VERSION 5.8 ;
BUSBITCHARS "[]" ;
DIVIDERCHAR "/" ;
UNITS
    DATABASE MICRONS 1000 ;
END UNITS

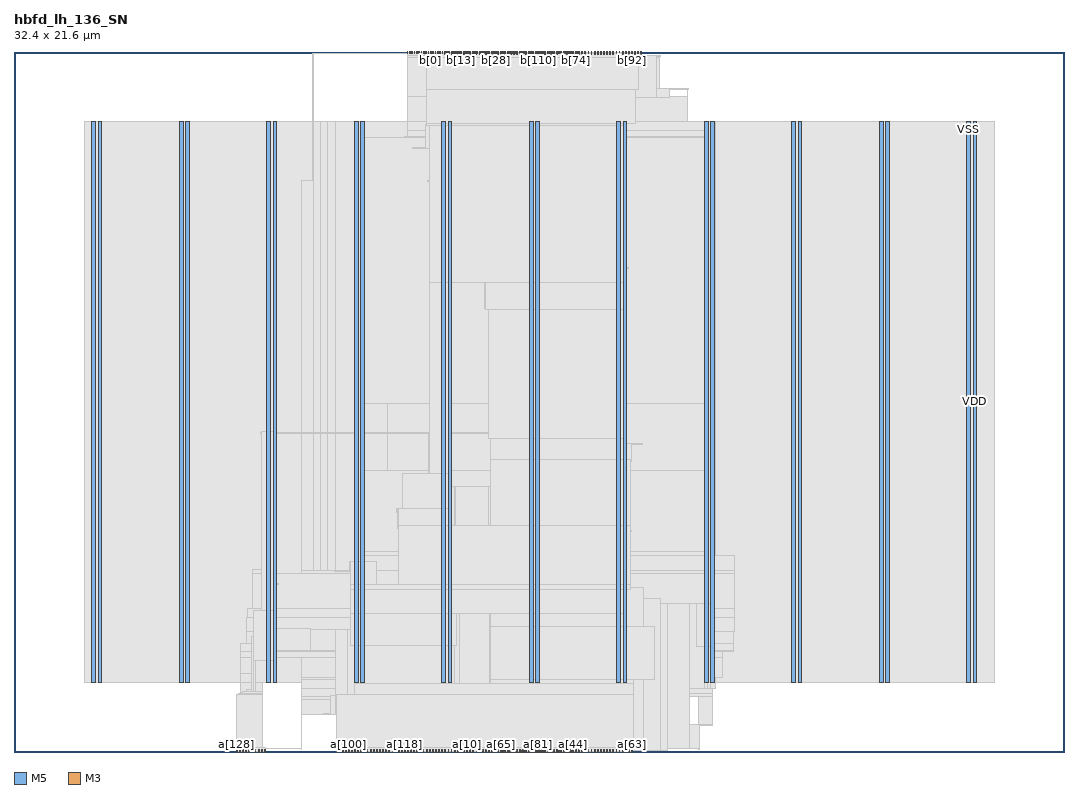
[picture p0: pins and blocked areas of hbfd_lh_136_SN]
MACRO hbfd_lh_136_SN
  FOREIGN hbfd_lh_136_SN 0 0 ;
  CLASS BLOCK ;
  SIZE 32.4 BY 21.6 ;
  PIN a[0]
    DIRECTION INPUT ;
    USE SIGNAL ;
    PORT
      LAYER M5 ;
        RECT  13.008 0 13.032 0.084 ;
    END
  END a[0]
  PIN a[100]
    DIRECTION INPUT ;
    USE SIGNAL ;
    PORT
      LAYER M5 ;
        RECT  10.32 0 10.344 0.084 ;
    END
  END a[100]
  PIN a[101]
    DIRECTION INPUT ;
    USE SIGNAL ;
    PORT
      LAYER M5 ;
        RECT  10.416 0 10.44 0.084 ;
    END
  END a[101]
  PIN a[102]
    DIRECTION INPUT ;
    USE SIGNAL ;
    PORT
      LAYER M5 ;
        RECT  10.512 0 10.536 0.084 ;
    END
  END a[102]
  PIN a[103]
    DIRECTION INPUT ;
    USE SIGNAL ;
    PORT
      LAYER M5 ;
        RECT  10.608 0 10.632 0.084 ;
    END
  END a[103]
  PIN a[104]
    DIRECTION INPUT ;
    USE SIGNAL ;
    PORT
      LAYER M5 ;
        RECT  10.704 0 10.728 0.084 ;
    END
  END a[104]
  PIN a[105]
    DIRECTION INPUT ;
    USE SIGNAL ;
    PORT
      LAYER M5 ;
        RECT  10.8 0 10.824 0.084 ;
    END
  END a[105]
  PIN a[106]
    DIRECTION INPUT ;
    USE SIGNAL ;
    PORT
      LAYER M5 ;
        RECT  10.896 0 10.92 0.084 ;
    END
  END a[106]
  PIN a[107]
    DIRECTION INPUT ;
    USE SIGNAL ;
    PORT
      LAYER M5 ;
        RECT  10.992 0 11.016 0.084 ;
    END
  END a[107]
  PIN a[108]
    DIRECTION INPUT ;
    USE SIGNAL ;
    PORT
      LAYER M5 ;
        RECT  11.088 0 11.112 0.084 ;
    END
  END a[108]
  PIN a[109]
    DIRECTION INPUT ;
    USE SIGNAL ;
    PORT
      LAYER M5 ;
        RECT  11.184 0 11.208 0.084 ;
    END
  END a[109]
  PIN a[10]
    DIRECTION INPUT ;
    USE SIGNAL ;
    PORT
      LAYER M5 ;
        RECT  13.968 0 13.992 0.084 ;
    END
  END a[10]
  PIN a[110]
    DIRECTION INPUT ;
    USE SIGNAL ;
    PORT
      LAYER M5 ;
        RECT  11.28 0 11.304 0.084 ;
    END
  END a[110]
  PIN a[111]
    DIRECTION INPUT ;
    USE SIGNAL ;
    PORT
      LAYER M5 ;
        RECT  11.376 0 11.4 0.084 ;
    END
  END a[111]
  PIN a[112]
    DIRECTION INPUT ;
    USE SIGNAL ;
    PORT
      LAYER M5 ;
        RECT  11.472 0 11.496 0.084 ;
    END
  END a[112]
  PIN a[113]
    DIRECTION INPUT ;
    USE SIGNAL ;
    PORT
      LAYER M5 ;
        RECT  11.568 0 11.592 0.084 ;
    END
  END a[113]
  PIN a[114]
    DIRECTION INPUT ;
    USE SIGNAL ;
    PORT
      LAYER M5 ;
        RECT  11.664 0 11.688 0.084 ;
    END
  END a[114]
  PIN a[115]
    DIRECTION INPUT ;
    USE SIGNAL ;
    PORT
      LAYER M5 ;
        RECT  11.76 0 11.784 0.084 ;
    END
  END a[115]
  PIN a[116]
    DIRECTION INPUT ;
    USE SIGNAL ;
    PORT
      LAYER M5 ;
        RECT  11.856 0 11.88 0.084 ;
    END
  END a[116]
  PIN a[117]
    DIRECTION INPUT ;
    USE SIGNAL ;
    PORT
      LAYER M5 ;
        RECT  11.952 0 11.976 0.084 ;
    END
  END a[117]
  PIN a[118]
    DIRECTION INPUT ;
    USE SIGNAL ;
    PORT
      LAYER M5 ;
        RECT  12.048 0 12.072 0.084 ;
    END
  END a[118]
  PIN a[119]
    DIRECTION INPUT ;
    USE SIGNAL ;
    PORT
      LAYER M5 ;
        RECT  12.144 0 12.168 0.084 ;
    END
  END a[119]
  PIN a[11]
    DIRECTION INPUT ;
    USE SIGNAL ;
    PORT
      LAYER M5 ;
        RECT  14.064 0 14.088 0.084 ;
    END
  END a[11]
  PIN a[120]
    DIRECTION INPUT ;
    USE SIGNAL ;
    PORT
      LAYER M5 ;
        RECT  12.24 0 12.264 0.084 ;
    END
  END a[120]
  PIN a[121]
    DIRECTION INPUT ;
    USE SIGNAL ;
    PORT
      LAYER M5 ;
        RECT  12.336 0 12.36 0.084 ;
    END
  END a[121]
  PIN a[122]
    DIRECTION INPUT ;
    USE SIGNAL ;
    PORT
      LAYER M5 ;
        RECT  12.432 0 12.456 0.084 ;
    END
  END a[122]
  PIN a[123]
    DIRECTION INPUT ;
    USE SIGNAL ;
    PORT
      LAYER M5 ;
        RECT  12.528 0 12.552 0.084 ;
    END
  END a[123]
  PIN a[124]
    DIRECTION INPUT ;
    USE SIGNAL ;
    PORT
      LAYER M5 ;
        RECT  12.624 0 12.648 0.084 ;
    END
  END a[124]
  PIN a[125]
    DIRECTION INPUT ;
    USE SIGNAL ;
    PORT
      LAYER M5 ;
        RECT  12.72 0 12.744 0.084 ;
    END
  END a[125]
  PIN a[126]
    DIRECTION INPUT ;
    USE SIGNAL ;
    PORT
      LAYER M5 ;
        RECT  12.816 0 12.84 0.084 ;
    END
  END a[126]
  PIN a[127]
    DIRECTION INPUT ;
    USE SIGNAL ;
    PORT
      LAYER M5 ;
        RECT  12.912 0 12.936 0.084 ;
    END
  END a[127]
  PIN a[128]
    DIRECTION INPUT ;
    USE SIGNAL ;
    PORT
      LAYER M5 ;
        RECT  6.864 0 6.888 0.084 ;
    END
  END a[128]
  PIN a[129]
    DIRECTION INPUT ;
    USE SIGNAL ;
    PORT
      LAYER M5 ;
        RECT  6.96 0 6.984 0.084 ;
    END
  END a[129]
  PIN a[12]
    DIRECTION INPUT ;
    USE SIGNAL ;
    PORT
      LAYER M5 ;
        RECT  14.16 0 14.184 0.084 ;
    END
  END a[12]
  PIN a[130]
    DIRECTION INPUT ;
    USE SIGNAL ;
    PORT
      LAYER M5 ;
        RECT  7.056 0 7.08 0.084 ;
    END
  END a[130]
  PIN a[131]
    DIRECTION INPUT ;
    USE SIGNAL ;
    PORT
      LAYER M5 ;
        RECT  7.152 0 7.176 0.084 ;
    END
  END a[131]
  PIN a[132]
    DIRECTION INPUT ;
    USE SIGNAL ;
    PORT
      LAYER M5 ;
        RECT  7.248 0 7.272 0.084 ;
    END
  END a[132]
  PIN a[133]
    DIRECTION INPUT ;
    USE SIGNAL ;
    PORT
      LAYER M5 ;
        RECT  7.344 0 7.368 0.084 ;
    END
  END a[133]
  PIN a[134]
    DIRECTION INPUT ;
    USE SIGNAL ;
    PORT
      LAYER M5 ;
        RECT  7.44 0 7.464 0.084 ;
    END
  END a[134]
  PIN a[135]
    DIRECTION INPUT ;
    USE SIGNAL ;
    PORT
      LAYER M5 ;
        RECT  7.536 0 7.56 0.084 ;
    END
  END a[135]
  PIN a[13]
    DIRECTION INPUT ;
    USE SIGNAL ;
    PORT
      LAYER M5 ;
        RECT  14.256 0 14.28 0.084 ;
    END
  END a[13]
  PIN a[14]
    DIRECTION INPUT ;
    USE SIGNAL ;
    PORT
      LAYER M5 ;
        RECT  14.352 0 14.376 0.084 ;
    END
  END a[14]
  PIN a[15]
    DIRECTION INPUT ;
    USE SIGNAL ;
    PORT
      LAYER M5 ;
        RECT  14.448 0 14.472 0.084 ;
    END
  END a[15]
  PIN a[16]
    DIRECTION INPUT ;
    USE SIGNAL ;
    PORT
      LAYER M5 ;
        RECT  14.544 0 14.568 0.084 ;
    END
  END a[16]
  PIN a[17]
    DIRECTION INPUT ;
    USE SIGNAL ;
    PORT
      LAYER M5 ;
        RECT  14.64 0 14.664 0.084 ;
    END
  END a[17]
  PIN a[18]
    DIRECTION INPUT ;
    USE SIGNAL ;
    PORT
      LAYER M5 ;
        RECT  14.736 0 14.76 0.084 ;
    END
  END a[18]
  PIN a[19]
    DIRECTION INPUT ;
    USE SIGNAL ;
    PORT
      LAYER M5 ;
        RECT  14.832 0 14.856 0.084 ;
    END
  END a[19]
  PIN a[1]
    DIRECTION INPUT ;
    USE SIGNAL ;
    PORT
      LAYER M5 ;
        RECT  13.104 0 13.128 0.084 ;
    END
  END a[1]
  PIN a[20]
    DIRECTION INPUT ;
    USE SIGNAL ;
    PORT
      LAYER M5 ;
        RECT  14.928 0 14.952 0.084 ;
    END
  END a[20]
  PIN a[21]
    DIRECTION INPUT ;
    USE SIGNAL ;
    PORT
      LAYER M5 ;
        RECT  15.024 0 15.048 0.084 ;
    END
  END a[21]
  PIN a[22]
    DIRECTION INPUT ;
    USE SIGNAL ;
    PORT
      LAYER M5 ;
        RECT  15.12 0 15.144 0.084 ;
    END
  END a[22]
  PIN a[23]
    DIRECTION INPUT ;
    USE SIGNAL ;
    PORT
      LAYER M5 ;
        RECT  15.216 0 15.24 0.084 ;
    END
  END a[23]
  PIN a[24]
    DIRECTION INPUT ;
    USE SIGNAL ;
    PORT
      LAYER M5 ;
        RECT  15.312 0 15.336 0.084 ;
    END
  END a[24]
  PIN a[25]
    DIRECTION INPUT ;
    USE SIGNAL ;
    PORT
      LAYER M5 ;
        RECT  15.408 0 15.432 0.084 ;
    END
  END a[25]
  PIN a[26]
    DIRECTION INPUT ;
    USE SIGNAL ;
    PORT
      LAYER M5 ;
        RECT  15.504 0 15.528 0.084 ;
    END
  END a[26]
  PIN a[27]
    DIRECTION INPUT ;
    USE SIGNAL ;
    PORT
      LAYER M5 ;
        RECT  15.6 0 15.624 0.084 ;
    END
  END a[27]
  PIN a[28]
    DIRECTION INPUT ;
    USE SIGNAL ;
    PORT
      LAYER M5 ;
        RECT  15.696 0 15.72 0.084 ;
    END
  END a[28]
  PIN a[29]
    DIRECTION INPUT ;
    USE SIGNAL ;
    PORT
      LAYER M5 ;
        RECT  15.792 0 15.816 0.084 ;
    END
  END a[29]
  PIN a[2]
    DIRECTION INPUT ;
    USE SIGNAL ;
    PORT
      LAYER M5 ;
        RECT  13.2 0 13.224 0.084 ;
    END
  END a[2]
  PIN a[30]
    DIRECTION INPUT ;
    USE SIGNAL ;
    PORT
      LAYER M5 ;
        RECT  15.888 0 15.912 0.084 ;
    END
  END a[30]
  PIN a[31]
    DIRECTION INPUT ;
    USE SIGNAL ;
    PORT
      LAYER M5 ;
        RECT  15.984 0 16.008 0.084 ;
    END
  END a[31]
  PIN a[32]
    DIRECTION INPUT ;
    USE SIGNAL ;
    PORT
      LAYER M5 ;
        RECT  16.08 0 16.104 0.084 ;
    END
  END a[32]
  PIN a[33]
    DIRECTION INPUT ;
    USE SIGNAL ;
    PORT
      LAYER M5 ;
        RECT  16.176 0 16.2 0.084 ;
    END
  END a[33]
  PIN a[34]
    DIRECTION INPUT ;
    USE SIGNAL ;
    PORT
      LAYER M5 ;
        RECT  16.272 0 16.296 0.084 ;
    END
  END a[34]
  PIN a[35]
    DIRECTION INPUT ;
    USE SIGNAL ;
    PORT
      LAYER M5 ;
        RECT  16.368 0 16.392 0.084 ;
    END
  END a[35]
  PIN a[36]
    DIRECTION INPUT ;
    USE SIGNAL ;
    PORT
      LAYER M5 ;
        RECT  16.464 0 16.488 0.084 ;
    END
  END a[36]
  PIN a[37]
    DIRECTION INPUT ;
    USE SIGNAL ;
    PORT
      LAYER M5 ;
        RECT  16.56 0 16.584 0.084 ;
    END
  END a[37]
  PIN a[38]
    DIRECTION INPUT ;
    USE SIGNAL ;
    PORT
      LAYER M5 ;
        RECT  16.656 0 16.68 0.084 ;
    END
  END a[38]
  PIN a[39]
    DIRECTION INPUT ;
    USE SIGNAL ;
    PORT
      LAYER M5 ;
        RECT  16.752 0 16.776 0.084 ;
    END
  END a[39]
  PIN a[3]
    DIRECTION INPUT ;
    USE SIGNAL ;
    PORT
      LAYER M5 ;
        RECT  13.296 0 13.32 0.084 ;
    END
  END a[3]
  PIN a[40]
    DIRECTION INPUT ;
    USE SIGNAL ;
    PORT
      LAYER M5 ;
        RECT  16.848 0 16.872 0.084 ;
    END
  END a[40]
  PIN a[41]
    DIRECTION INPUT ;
    USE SIGNAL ;
    PORT
      LAYER M5 ;
        RECT  16.944 0 16.968 0.084 ;
    END
  END a[41]
  PIN a[42]
    DIRECTION INPUT ;
    USE SIGNAL ;
    PORT
      LAYER M5 ;
        RECT  17.04 0 17.064 0.084 ;
    END
  END a[42]
  PIN a[43]
    DIRECTION INPUT ;
    USE SIGNAL ;
    PORT
      LAYER M5 ;
        RECT  17.136 0 17.16 0.084 ;
    END
  END a[43]
  PIN a[44]
    DIRECTION INPUT ;
    USE SIGNAL ;
    PORT
      LAYER M5 ;
        RECT  17.232 0 17.256 0.084 ;
    END
  END a[44]
  PIN a[45]
    DIRECTION INPUT ;
    USE SIGNAL ;
    PORT
      LAYER M5 ;
        RECT  17.328 0 17.352 0.084 ;
    END
  END a[45]
  PIN a[46]
    DIRECTION INPUT ;
    USE SIGNAL ;
    PORT
      LAYER M5 ;
        RECT  17.424 0 17.448 0.084 ;
    END
  END a[46]
  PIN a[47]
    DIRECTION INPUT ;
    USE SIGNAL ;
    PORT
      LAYER M5 ;
        RECT  17.52 0 17.544 0.084 ;
    END
  END a[47]
  PIN a[48]
    DIRECTION INPUT ;
    USE SIGNAL ;
    PORT
      LAYER M5 ;
        RECT  17.616 0 17.64 0.084 ;
    END
  END a[48]
  PIN a[49]
    DIRECTION INPUT ;
    USE SIGNAL ;
    PORT
      LAYER M5 ;
        RECT  17.712 0 17.736 0.084 ;
    END
  END a[49]
  PIN a[4]
    DIRECTION INPUT ;
    USE SIGNAL ;
    PORT
      LAYER M5 ;
        RECT  13.392 0 13.416 0.084 ;
    END
  END a[4]
  PIN a[50]
    DIRECTION INPUT ;
    USE SIGNAL ;
    PORT
      LAYER M5 ;
        RECT  17.808 0 17.832 0.084 ;
    END
  END a[50]
  PIN a[51]
    DIRECTION INPUT ;
    USE SIGNAL ;
    PORT
      LAYER M5 ;
        RECT  17.904 0 17.928 0.084 ;
    END
  END a[51]
  PIN a[52]
    DIRECTION INPUT ;
    USE SIGNAL ;
    PORT
      LAYER M5 ;
        RECT  18 0 18.024 0.084 ;
    END
  END a[52]
  PIN a[53]
    DIRECTION INPUT ;
    USE SIGNAL ;
    PORT
      LAYER M5 ;
        RECT  18.096 0 18.12 0.084 ;
    END
  END a[53]
  PIN a[54]
    DIRECTION INPUT ;
    USE SIGNAL ;
    PORT
      LAYER M5 ;
        RECT  18.192 0 18.216 0.084 ;
    END
  END a[54]
  PIN a[55]
    DIRECTION INPUT ;
    USE SIGNAL ;
    PORT
      LAYER M5 ;
        RECT  18.288 0 18.312 0.084 ;
    END
  END a[55]
  PIN a[56]
    DIRECTION INPUT ;
    USE SIGNAL ;
    PORT
      LAYER M5 ;
        RECT  18.384 0 18.408 0.084 ;
    END
  END a[56]
  PIN a[57]
    DIRECTION INPUT ;
    USE SIGNAL ;
    PORT
      LAYER M5 ;
        RECT  18.48 0 18.504 0.084 ;
    END
  END a[57]
  PIN a[58]
    DIRECTION INPUT ;
    USE SIGNAL ;
    PORT
      LAYER M5 ;
        RECT  18.576 0 18.6 0.084 ;
    END
  END a[58]
  PIN a[59]
    DIRECTION INPUT ;
    USE SIGNAL ;
    PORT
      LAYER M5 ;
        RECT  18.672 0 18.696 0.084 ;
    END
  END a[59]
  PIN a[5]
    DIRECTION INPUT ;
    USE SIGNAL ;
    PORT
      LAYER M5 ;
        RECT  13.488 0 13.512 0.084 ;
    END
  END a[5]
  PIN a[60]
    DIRECTION INPUT ;
    USE SIGNAL ;
    PORT
      LAYER M5 ;
        RECT  18.768 0 18.792 0.084 ;
    END
  END a[60]
  PIN a[61]
    DIRECTION INPUT ;
    USE SIGNAL ;
    PORT
      LAYER M5 ;
        RECT  18.864 0 18.888 0.084 ;
    END
  END a[61]
  PIN a[62]
    DIRECTION INPUT ;
    USE SIGNAL ;
    PORT
      LAYER M5 ;
        RECT  18.96 0 18.984 0.084 ;
    END
  END a[62]
  PIN a[63]
    DIRECTION INPUT ;
    USE SIGNAL ;
    PORT
      LAYER M5 ;
        RECT  19.056 0 19.08 0.084 ;
    END
  END a[63]
  PIN a[64]
    DIRECTION INPUT ;
    USE SIGNAL ;
    PORT
      LAYER M3 ;
        RECT  14.94 0 14.958 0.037 ;
    END
  END a[64]
  PIN a[65]
    DIRECTION INPUT ;
    USE SIGNAL ;
    PORT
      LAYER M3 ;
        RECT  15.012 0 15.03 0.037 ;
    END
  END a[65]
  PIN a[66]
    DIRECTION INPUT ;
    USE SIGNAL ;
    PORT
      LAYER M3 ;
        RECT  15.084 0 15.102 0.037 ;
    END
  END a[66]
  PIN a[67]
    DIRECTION INPUT ;
    USE SIGNAL ;
    PORT
      LAYER M3 ;
        RECT  15.156 0 15.174 0.037 ;
    END
  END a[67]
  PIN a[68]
    DIRECTION INPUT ;
    USE SIGNAL ;
    PORT
      LAYER M3 ;
        RECT  15.228 0 15.246 0.037 ;
    END
  END a[68]
  PIN a[69]
    DIRECTION INPUT ;
    USE SIGNAL ;
    PORT
      LAYER M3 ;
        RECT  15.3 0 15.318 0.037 ;
    END
  END a[69]
  PIN a[6]
    DIRECTION INPUT ;
    USE SIGNAL ;
    PORT
      LAYER M5 ;
        RECT  13.584 0 13.608 0.084 ;
    END
  END a[6]
  PIN a[70]
    DIRECTION INPUT ;
    USE SIGNAL ;
    PORT
      LAYER M3 ;
        RECT  15.372 0 15.39 0.037 ;
    END
  END a[70]
  PIN a[71]
    DIRECTION INPUT ;
    USE SIGNAL ;
    PORT
      LAYER M3 ;
        RECT  15.444 0 15.462 0.037 ;
    END
  END a[71]
  PIN a[72]
    DIRECTION INPUT ;
    USE SIGNAL ;
    PORT
      LAYER M3 ;
        RECT  15.516 0 15.534 0.037 ;
    END
  END a[72]
  PIN a[73]
    DIRECTION INPUT ;
    USE SIGNAL ;
    PORT
      LAYER M3 ;
        RECT  15.588 0 15.606 0.037 ;
    END
  END a[73]
  PIN a[74]
    DIRECTION INPUT ;
    USE SIGNAL ;
    PORT
      LAYER M3 ;
        RECT  15.66 0 15.678 0.037 ;
    END
  END a[74]
  PIN a[75]
    DIRECTION INPUT ;
    USE SIGNAL ;
    PORT
      LAYER M3 ;
        RECT  15.732 0 15.75 0.037 ;
    END
  END a[75]
  PIN a[76]
    DIRECTION INPUT ;
    USE SIGNAL ;
    PORT
      LAYER M3 ;
        RECT  15.804 0 15.822 0.037 ;
    END
  END a[76]
  PIN a[77]
    DIRECTION INPUT ;
    USE SIGNAL ;
    PORT
      LAYER M3 ;
        RECT  15.876 0 15.894 0.037 ;
    END
  END a[77]
  PIN a[78]
    DIRECTION INPUT ;
    USE SIGNAL ;
    PORT
      LAYER M3 ;
        RECT  15.948 0 15.966 0.037 ;
    END
  END a[78]
  PIN a[79]
    DIRECTION INPUT ;
    USE SIGNAL ;
    PORT
      LAYER M3 ;
        RECT  16.02 0 16.038 0.037 ;
    END
  END a[79]
  PIN a[7]
    DIRECTION INPUT ;
    USE SIGNAL ;
    PORT
      LAYER M5 ;
        RECT  13.68 0 13.704 0.084 ;
    END
  END a[7]
  PIN a[80]
    DIRECTION INPUT ;
    USE SIGNAL ;
    PORT
      LAYER M3 ;
        RECT  16.092 0 16.11 0.037 ;
    END
  END a[80]
  PIN a[81]
    DIRECTION INPUT ;
    USE SIGNAL ;
    PORT
      LAYER M3 ;
        RECT  16.164 0 16.182 0.037 ;
    END
  END a[81]
  PIN a[82]
    DIRECTION INPUT ;
    USE SIGNAL ;
    PORT
      LAYER M3 ;
        RECT  16.236 0 16.254 0.037 ;
    END
  END a[82]
  PIN a[83]
    DIRECTION INPUT ;
    USE SIGNAL ;
    PORT
      LAYER M3 ;
        RECT  16.308 0 16.326 0.037 ;
    END
  END a[83]
  PIN a[84]
    DIRECTION INPUT ;
    USE SIGNAL ;
    PORT
      LAYER M3 ;
        RECT  16.38 0 16.398 0.037 ;
    END
  END a[84]
  PIN a[85]
    DIRECTION INPUT ;
    USE SIGNAL ;
    PORT
      LAYER M3 ;
        RECT  16.452 0 16.47 0.037 ;
    END
  END a[85]
  PIN a[86]
    DIRECTION INPUT ;
    USE SIGNAL ;
    PORT
      LAYER M3 ;
        RECT  16.524 0 16.542 0.037 ;
    END
  END a[86]
  PIN a[87]
    DIRECTION INPUT ;
    USE SIGNAL ;
    PORT
      LAYER M3 ;
        RECT  16.596 0 16.614 0.037 ;
    END
  END a[87]
  PIN a[88]
    DIRECTION INPUT ;
    USE SIGNAL ;
    PORT
      LAYER M3 ;
        RECT  16.668 0 16.686 0.037 ;
    END
  END a[88]
  PIN a[89]
    DIRECTION INPUT ;
    USE SIGNAL ;
    PORT
      LAYER M3 ;
        RECT  16.74 0 16.758 0.037 ;
    END
  END a[89]
  PIN a[8]
    DIRECTION INPUT ;
    USE SIGNAL ;
    PORT
      LAYER M5 ;
        RECT  13.776 0 13.8 0.084 ;
    END
  END a[8]
  PIN a[90]
    DIRECTION INPUT ;
    USE SIGNAL ;
    PORT
      LAYER M3 ;
        RECT  16.812 0 16.83 0.037 ;
    END
  END a[90]
  PIN a[91]
    DIRECTION INPUT ;
    USE SIGNAL ;
    PORT
      LAYER M3 ;
        RECT  16.884 0 16.902 0.037 ;
    END
  END a[91]
  PIN a[92]
    DIRECTION INPUT ;
    USE SIGNAL ;
    PORT
      LAYER M3 ;
        RECT  16.956 0 16.974 0.037 ;
    END
  END a[92]
  PIN a[93]
    DIRECTION INPUT ;
    USE SIGNAL ;
    PORT
      LAYER M3 ;
        RECT  17.028 0 17.046 0.037 ;
    END
  END a[93]
  PIN a[94]
    DIRECTION INPUT ;
    USE SIGNAL ;
    PORT
      LAYER M3 ;
        RECT  17.1 0 17.118 0.037 ;
    END
  END a[94]
  PIN a[95]
    DIRECTION INPUT ;
    USE SIGNAL ;
    PORT
      LAYER M3 ;
        RECT  17.172 0 17.19 0.037 ;
    END
  END a[95]
  PIN a[96]
    DIRECTION INPUT ;
    USE SIGNAL ;
    PORT
      LAYER M5 ;
        RECT  9.936 0 9.96 0.084 ;
    END
  END a[96]
  PIN a[97]
    DIRECTION INPUT ;
    USE SIGNAL ;
    PORT
      LAYER M5 ;
        RECT  10.032 0 10.056 0.084 ;
    END
  END a[97]
  PIN a[98]
    DIRECTION INPUT ;
    USE SIGNAL ;
    PORT
      LAYER M5 ;
        RECT  10.128 0 10.152 0.084 ;
    END
  END a[98]
  PIN a[99]
    DIRECTION INPUT ;
    USE SIGNAL ;
    PORT
      LAYER M5 ;
        RECT  10.224 0 10.248 0.084 ;
    END
  END a[99]
  PIN a[9]
    DIRECTION INPUT ;
    USE SIGNAL ;
    PORT
      LAYER M5 ;
        RECT  13.872 0 13.896 0.084 ;
    END
  END a[9]
  PIN b[0]
    DIRECTION OUTPUT ;
    USE SIGNAL ;
    PORT
      LAYER M3 ;
        RECT  12.852 21.563 12.87 21.6 ;
    END
  END b[0]
  PIN b[100]
    DIRECTION OUTPUT ;
    USE SIGNAL ;
    PORT
      LAYER M3 ;
        RECT  15.444 21.563 15.462 21.6 ;
    END
  END b[100]
  PIN b[101]
    DIRECTION OUTPUT ;
    USE SIGNAL ;
    PORT
      LAYER M3 ;
        RECT  15.516 21.563 15.534 21.6 ;
    END
  END b[101]
  PIN b[102]
    DIRECTION OUTPUT ;
    USE SIGNAL ;
    PORT
      LAYER M3 ;
        RECT  15.588 21.563 15.606 21.6 ;
    END
  END b[102]
  PIN b[103]
    DIRECTION OUTPUT ;
    USE SIGNAL ;
    PORT
      LAYER M3 ;
        RECT  15.66 21.563 15.678 21.6 ;
    END
  END b[103]
  PIN b[104]
    DIRECTION OUTPUT ;
    USE SIGNAL ;
    PORT
      LAYER M3 ;
        RECT  15.732 21.563 15.75 21.6 ;
    END
  END b[104]
  PIN b[105]
    DIRECTION OUTPUT ;
    USE SIGNAL ;
    PORT
      LAYER M3 ;
        RECT  15.804 21.563 15.822 21.6 ;
    END
  END b[105]
  PIN b[106]
    DIRECTION OUTPUT ;
    USE SIGNAL ;
    PORT
      LAYER M3 ;
        RECT  15.876 21.563 15.894 21.6 ;
    END
  END b[106]
  PIN b[107]
    DIRECTION OUTPUT ;
    USE SIGNAL ;
    PORT
      LAYER M3 ;
        RECT  15.948 21.563 15.966 21.6 ;
    END
  END b[107]
  PIN b[108]
    DIRECTION OUTPUT ;
    USE SIGNAL ;
    PORT
      LAYER M3 ;
        RECT  16.02 21.563 16.038 21.6 ;
    END
  END b[108]
  PIN b[109]
    DIRECTION OUTPUT ;
    USE SIGNAL ;
    PORT
      LAYER M3 ;
        RECT  16.092 21.563 16.11 21.6 ;
    END
  END b[109]
  PIN b[10]
    DIRECTION OUTPUT ;
    USE SIGNAL ;
    PORT
      LAYER M3 ;
        RECT  13.572 21.563 13.59 21.6 ;
    END
  END b[10]
  PIN b[110]
    DIRECTION OUTPUT ;
    USE SIGNAL ;
    PORT
      LAYER M3 ;
        RECT  16.164 21.563 16.182 21.6 ;
    END
  END b[110]
  PIN b[111]
    DIRECTION OUTPUT ;
    USE SIGNAL ;
    PORT
      LAYER M3 ;
        RECT  16.236 21.563 16.254 21.6 ;
    END
  END b[111]
  PIN b[112]
    DIRECTION OUTPUT ;
    USE SIGNAL ;
    PORT
      LAYER M3 ;
        RECT  16.308 21.563 16.326 21.6 ;
    END
  END b[112]
  PIN b[113]
    DIRECTION OUTPUT ;
    USE SIGNAL ;
    PORT
      LAYER M3 ;
        RECT  16.38 21.563 16.398 21.6 ;
    END
  END b[113]
  PIN b[114]
    DIRECTION OUTPUT ;
    USE SIGNAL ;
    PORT
      LAYER M3 ;
        RECT  16.452 21.563 16.47 21.6 ;
    END
  END b[114]
  PIN b[115]
    DIRECTION OUTPUT ;
    USE SIGNAL ;
    PORT
      LAYER M3 ;
        RECT  16.524 21.563 16.542 21.6 ;
    END
  END b[115]
  PIN b[116]
    DIRECTION OUTPUT ;
    USE SIGNAL ;
    PORT
      LAYER M3 ;
        RECT  16.596 21.563 16.614 21.6 ;
    END
  END b[116]
  PIN b[117]
    DIRECTION OUTPUT ;
    USE SIGNAL ;
    PORT
      LAYER M3 ;
        RECT  16.668 21.563 16.686 21.6 ;
    END
  END b[117]
  PIN b[118]
    DIRECTION OUTPUT ;
    USE SIGNAL ;
    PORT
      LAYER M3 ;
        RECT  16.74 21.563 16.758 21.6 ;
    END
  END b[118]
  PIN b[119]
    DIRECTION OUTPUT ;
    USE SIGNAL ;
    PORT
      LAYER M3 ;
        RECT  16.812 21.563 16.83 21.6 ;
    END
  END b[119]
  PIN b[11]
    DIRECTION OUTPUT ;
    USE SIGNAL ;
    PORT
      LAYER M3 ;
        RECT  13.644 21.563 13.662 21.6 ;
    END
  END b[11]
  PIN b[120]
    DIRECTION OUTPUT ;
    USE SIGNAL ;
    PORT
      LAYER M3 ;
        RECT  16.884 21.563 16.902 21.6 ;
    END
  END b[120]
  PIN b[121]
    DIRECTION OUTPUT ;
    USE SIGNAL ;
    PORT
      LAYER M3 ;
        RECT  16.956 21.563 16.974 21.6 ;
    END
  END b[121]
  PIN b[122]
    DIRECTION OUTPUT ;
    USE SIGNAL ;
    PORT
      LAYER M3 ;
        RECT  17.028 21.563 17.046 21.6 ;
    END
  END b[122]
  PIN b[123]
    DIRECTION OUTPUT ;
    USE SIGNAL ;
    PORT
      LAYER M3 ;
        RECT  17.1 21.563 17.118 21.6 ;
    END
  END b[123]
  PIN b[124]
    DIRECTION OUTPUT ;
    USE SIGNAL ;
    PORT
      LAYER M3 ;
        RECT  17.172 21.563 17.19 21.6 ;
    END
  END b[124]
  PIN b[125]
    DIRECTION OUTPUT ;
    USE SIGNAL ;
    PORT
      LAYER M3 ;
        RECT  17.244 21.563 17.262 21.6 ;
    END
  END b[125]
  PIN b[126]
    DIRECTION OUTPUT ;
    USE SIGNAL ;
    PORT
      LAYER M3 ;
        RECT  17.316 21.563 17.334 21.6 ;
    END
  END b[126]
  PIN b[127]
    DIRECTION OUTPUT ;
    USE SIGNAL ;
    PORT
      LAYER M3 ;
        RECT  17.388 21.563 17.406 21.6 ;
    END
  END b[127]
  PIN b[128]
    DIRECTION OUTPUT ;
    USE SIGNAL ;
    PORT
      LAYER M3 ;
        RECT  12.132 21.563 12.15 21.6 ;
    END
  END b[128]
  PIN b[129]
    DIRECTION OUTPUT ;
    USE SIGNAL ;
    PORT
      LAYER M3 ;
        RECT  12.204 21.563 12.222 21.6 ;
    END
  END b[129]
  PIN b[12]
    DIRECTION OUTPUT ;
    USE SIGNAL ;
    PORT
      LAYER M3 ;
        RECT  13.716 21.563 13.734 21.6 ;
    END
  END b[12]
  PIN b[130]
    DIRECTION OUTPUT ;
    USE SIGNAL ;
    PORT
      LAYER M3 ;
        RECT  12.276 21.563 12.294 21.6 ;
    END
  END b[130]
  PIN b[131]
    DIRECTION OUTPUT ;
    USE SIGNAL ;
    PORT
      LAYER M3 ;
        RECT  12.348 21.563 12.366 21.6 ;
    END
  END b[131]
  PIN b[132]
    DIRECTION OUTPUT ;
    USE SIGNAL ;
    PORT
      LAYER M3 ;
        RECT  12.42 21.563 12.438 21.6 ;
    END
  END b[132]
  PIN b[133]
    DIRECTION OUTPUT ;
    USE SIGNAL ;
    PORT
      LAYER M3 ;
        RECT  12.492 21.563 12.51 21.6 ;
    END
  END b[133]
  PIN b[134]
    DIRECTION OUTPUT ;
    USE SIGNAL ;
    PORT
      LAYER M3 ;
        RECT  12.564 21.563 12.582 21.6 ;
    END
  END b[134]
  PIN b[135]
    DIRECTION OUTPUT ;
    USE SIGNAL ;
    PORT
      LAYER M3 ;
        RECT  12.636 21.563 12.654 21.6 ;
    END
  END b[135]
  PIN b[13]
    DIRECTION OUTPUT ;
    USE SIGNAL ;
    PORT
      LAYER M3 ;
        RECT  13.788 21.563 13.806 21.6 ;
    END
  END b[13]
  PIN b[14]
    DIRECTION OUTPUT ;
    USE SIGNAL ;
    PORT
      LAYER M3 ;
        RECT  13.86 21.563 13.878 21.6 ;
    END
  END b[14]
  PIN b[15]
    DIRECTION OUTPUT ;
    USE SIGNAL ;
    PORT
      LAYER M3 ;
        RECT  13.932 21.563 13.95 21.6 ;
    END
  END b[15]
  PIN b[16]
    DIRECTION OUTPUT ;
    USE SIGNAL ;
    PORT
      LAYER M3 ;
        RECT  14.004 21.563 14.022 21.6 ;
    END
  END b[16]
  PIN b[17]
    DIRECTION OUTPUT ;
    USE SIGNAL ;
    PORT
      LAYER M3 ;
        RECT  14.076 21.563 14.094 21.6 ;
    END
  END b[17]
  PIN b[18]
    DIRECTION OUTPUT ;
    USE SIGNAL ;
    PORT
      LAYER M3 ;
        RECT  14.148 21.563 14.166 21.6 ;
    END
  END b[18]
  PIN b[19]
    DIRECTION OUTPUT ;
    USE SIGNAL ;
    PORT
      LAYER M3 ;
        RECT  14.22 21.563 14.238 21.6 ;
    END
  END b[19]
  PIN b[1]
    DIRECTION OUTPUT ;
    USE SIGNAL ;
    PORT
      LAYER M3 ;
        RECT  12.924 21.563 12.942 21.6 ;
    END
  END b[1]
  PIN b[20]
    DIRECTION OUTPUT ;
    USE SIGNAL ;
    PORT
      LAYER M3 ;
        RECT  14.292 21.563 14.31 21.6 ;
    END
  END b[20]
  PIN b[21]
    DIRECTION OUTPUT ;
    USE SIGNAL ;
    PORT
      LAYER M3 ;
        RECT  14.364 21.563 14.382 21.6 ;
    END
  END b[21]
  PIN b[22]
    DIRECTION OUTPUT ;
    USE SIGNAL ;
    PORT
      LAYER M3 ;
        RECT  14.436 21.563 14.454 21.6 ;
    END
  END b[22]
  PIN b[23]
    DIRECTION OUTPUT ;
    USE SIGNAL ;
    PORT
      LAYER M3 ;
        RECT  14.508 21.563 14.526 21.6 ;
    END
  END b[23]
  PIN b[24]
    DIRECTION OUTPUT ;
    USE SIGNAL ;
    PORT
      LAYER M3 ;
        RECT  14.58 21.563 14.598 21.6 ;
    END
  END b[24]
  PIN b[25]
    DIRECTION OUTPUT ;
    USE SIGNAL ;
    PORT
      LAYER M3 ;
        RECT  14.652 21.563 14.67 21.6 ;
    END
  END b[25]
  PIN b[26]
    DIRECTION OUTPUT ;
    USE SIGNAL ;
    PORT
      LAYER M3 ;
        RECT  14.724 21.563 14.742 21.6 ;
    END
  END b[26]
  PIN b[27]
    DIRECTION OUTPUT ;
    USE SIGNAL ;
    PORT
      LAYER M3 ;
        RECT  14.796 21.563 14.814 21.6 ;
    END
  END b[27]
  PIN b[28]
    DIRECTION OUTPUT ;
    USE SIGNAL ;
    PORT
      LAYER M3 ;
        RECT  14.868 21.563 14.886 21.6 ;
    END
  END b[28]
  PIN b[29]
    DIRECTION OUTPUT ;
    USE SIGNAL ;
    PORT
      LAYER M3 ;
        RECT  14.94 21.563 14.958 21.6 ;
    END
  END b[29]
  PIN b[2]
    DIRECTION OUTPUT ;
    USE SIGNAL ;
    PORT
      LAYER M3 ;
        RECT  12.996 21.563 13.014 21.6 ;
    END
  END b[2]
  PIN b[30]
    DIRECTION OUTPUT ;
    USE SIGNAL ;
    PORT
      LAYER M3 ;
        RECT  15.012 21.563 15.03 21.6 ;
    END
  END b[30]
  PIN b[31]
    DIRECTION OUTPUT ;
    USE SIGNAL ;
    PORT
      LAYER M3 ;
        RECT  15.084 21.563 15.102 21.6 ;
    END
  END b[31]
  PIN b[32]
    DIRECTION OUTPUT ;
    USE SIGNAL ;
    PORT
      LAYER M5 ;
        RECT  13.296 21.516 13.32 21.6 ;
    END
  END b[32]
  PIN b[33]
    DIRECTION OUTPUT ;
    USE SIGNAL ;
    PORT
      LAYER M5 ;
        RECT  13.392 21.516 13.416 21.6 ;
    END
  END b[33]
  PIN b[34]
    DIRECTION OUTPUT ;
    USE SIGNAL ;
    PORT
      LAYER M5 ;
        RECT  13.488 21.516 13.512 21.6 ;
    END
  END b[34]
  PIN b[35]
    DIRECTION OUTPUT ;
    USE SIGNAL ;
    PORT
      LAYER M5 ;
        RECT  13.584 21.516 13.608 21.6 ;
    END
  END b[35]
  PIN b[36]
    DIRECTION OUTPUT ;
    USE SIGNAL ;
    PORT
      LAYER M5 ;
        RECT  13.68 21.516 13.704 21.6 ;
    END
  END b[36]
  PIN b[37]
    DIRECTION OUTPUT ;
    USE SIGNAL ;
    PORT
      LAYER M5 ;
        RECT  13.776 21.516 13.8 21.6 ;
    END
  END b[37]
  PIN b[38]
    DIRECTION OUTPUT ;
    USE SIGNAL ;
    PORT
      LAYER M5 ;
        RECT  13.872 21.516 13.896 21.6 ;
    END
  END b[38]
  PIN b[39]
    DIRECTION OUTPUT ;
    USE SIGNAL ;
    PORT
      LAYER M5 ;
        RECT  13.968 21.516 13.992 21.6 ;
    END
  END b[39]
  PIN b[3]
    DIRECTION OUTPUT ;
    USE SIGNAL ;
    PORT
      LAYER M3 ;
        RECT  13.068 21.563 13.086 21.6 ;
    END
  END b[3]
  PIN b[40]
    DIRECTION OUTPUT ;
    USE SIGNAL ;
    PORT
      LAYER M5 ;
        RECT  14.064 21.516 14.088 21.6 ;
    END
  END b[40]
  PIN b[41]
    DIRECTION OUTPUT ;
    USE SIGNAL ;
    PORT
      LAYER M5 ;
        RECT  14.16 21.516 14.184 21.6 ;
    END
  END b[41]
  PIN b[42]
    DIRECTION OUTPUT ;
    USE SIGNAL ;
    PORT
      LAYER M5 ;
        RECT  14.256 21.516 14.28 21.6 ;
    END
  END b[42]
  PIN b[43]
    DIRECTION OUTPUT ;
    USE SIGNAL ;
    PORT
      LAYER M5 ;
        RECT  14.352 21.516 14.376 21.6 ;
    END
  END b[43]
  PIN b[44]
    DIRECTION OUTPUT ;
    USE SIGNAL ;
    PORT
      LAYER M5 ;
        RECT  14.448 21.516 14.472 21.6 ;
    END
  END b[44]
  PIN b[45]
    DIRECTION OUTPUT ;
    USE SIGNAL ;
    PORT
      LAYER M5 ;
        RECT  14.544 21.516 14.568 21.6 ;
    END
  END b[45]
  PIN b[46]
    DIRECTION OUTPUT ;
    USE SIGNAL ;
    PORT
      LAYER M5 ;
        RECT  14.64 21.516 14.664 21.6 ;
    END
  END b[46]
  PIN b[47]
    DIRECTION OUTPUT ;
    USE SIGNAL ;
    PORT
      LAYER M5 ;
        RECT  14.736 21.516 14.76 21.6 ;
    END
  END b[47]
  PIN b[48]
    DIRECTION OUTPUT ;
    USE SIGNAL ;
    PORT
      LAYER M5 ;
        RECT  14.832 21.516 14.856 21.6 ;
    END
  END b[48]
  PIN b[49]
    DIRECTION OUTPUT ;
    USE SIGNAL ;
    PORT
      LAYER M5 ;
        RECT  14.928 21.516 14.952 21.6 ;
    END
  END b[49]
  PIN b[4]
    DIRECTION OUTPUT ;
    USE SIGNAL ;
    PORT
      LAYER M3 ;
        RECT  13.14 21.563 13.158 21.6 ;
    END
  END b[4]
  PIN b[50]
    DIRECTION OUTPUT ;
    USE SIGNAL ;
    PORT
      LAYER M5 ;
        RECT  15.024 21.516 15.048 21.6 ;
    END
  END b[50]
  PIN b[51]
    DIRECTION OUTPUT ;
    USE SIGNAL ;
    PORT
      LAYER M5 ;
        RECT  15.12 21.516 15.144 21.6 ;
    END
  END b[51]
  PIN b[52]
    DIRECTION OUTPUT ;
    USE SIGNAL ;
    PORT
      LAYER M5 ;
        RECT  15.216 21.516 15.24 21.6 ;
    END
  END b[52]
  PIN b[53]
    DIRECTION OUTPUT ;
    USE SIGNAL ;
    PORT
      LAYER M5 ;
        RECT  15.312 21.516 15.336 21.6 ;
    END
  END b[53]
  PIN b[54]
    DIRECTION OUTPUT ;
    USE SIGNAL ;
    PORT
      LAYER M5 ;
        RECT  15.408 21.516 15.432 21.6 ;
    END
  END b[54]
  PIN b[55]
    DIRECTION OUTPUT ;
    USE SIGNAL ;
    PORT
      LAYER M5 ;
        RECT  15.504 21.516 15.528 21.6 ;
    END
  END b[55]
  PIN b[56]
    DIRECTION OUTPUT ;
    USE SIGNAL ;
    PORT
      LAYER M5 ;
        RECT  15.6 21.516 15.624 21.6 ;
    END
  END b[56]
  PIN b[57]
    DIRECTION OUTPUT ;
    USE SIGNAL ;
    PORT
      LAYER M5 ;
        RECT  15.696 21.516 15.72 21.6 ;
    END
  END b[57]
  PIN b[58]
    DIRECTION OUTPUT ;
    USE SIGNAL ;
    PORT
      LAYER M5 ;
        RECT  15.792 21.516 15.816 21.6 ;
    END
  END b[58]
  PIN b[59]
    DIRECTION OUTPUT ;
    USE SIGNAL ;
    PORT
      LAYER M5 ;
        RECT  15.888 21.516 15.912 21.6 ;
    END
  END b[59]
  PIN b[5]
    DIRECTION OUTPUT ;
    USE SIGNAL ;
    PORT
      LAYER M3 ;
        RECT  13.212 21.563 13.23 21.6 ;
    END
  END b[5]
  PIN b[60]
    DIRECTION OUTPUT ;
    USE SIGNAL ;
    PORT
      LAYER M5 ;
        RECT  15.984 21.516 16.008 21.6 ;
    END
  END b[60]
  PIN b[61]
    DIRECTION OUTPUT ;
    USE SIGNAL ;
    PORT
      LAYER M5 ;
        RECT  16.08 21.516 16.104 21.6 ;
    END
  END b[61]
  PIN b[62]
    DIRECTION OUTPUT ;
    USE SIGNAL ;
    PORT
      LAYER M5 ;
        RECT  16.176 21.516 16.2 21.6 ;
    END
  END b[62]
  PIN b[63]
    DIRECTION OUTPUT ;
    USE SIGNAL ;
    PORT
      LAYER M5 ;
        RECT  16.272 21.516 16.296 21.6 ;
    END
  END b[63]
  PIN b[64]
    DIRECTION OUTPUT ;
    USE SIGNAL ;
    PORT
      LAYER M5 ;
        RECT  16.368 21.516 16.392 21.6 ;
    END
  END b[64]
  PIN b[65]
    DIRECTION OUTPUT ;
    USE SIGNAL ;
    PORT
      LAYER M5 ;
        RECT  16.464 21.516 16.488 21.6 ;
    END
  END b[65]
  PIN b[66]
    DIRECTION OUTPUT ;
    USE SIGNAL ;
    PORT
      LAYER M5 ;
        RECT  16.56 21.516 16.584 21.6 ;
    END
  END b[66]
  PIN b[67]
    DIRECTION OUTPUT ;
    USE SIGNAL ;
    PORT
      LAYER M5 ;
        RECT  16.656 21.516 16.68 21.6 ;
    END
  END b[67]
  PIN b[68]
    DIRECTION OUTPUT ;
    USE SIGNAL ;
    PORT
      LAYER M5 ;
        RECT  16.752 21.516 16.776 21.6 ;
    END
  END b[68]
  PIN b[69]
    DIRECTION OUTPUT ;
    USE SIGNAL ;
    PORT
      LAYER M5 ;
        RECT  16.848 21.516 16.872 21.6 ;
    END
  END b[69]
  PIN b[6]
    DIRECTION OUTPUT ;
    USE SIGNAL ;
    PORT
      LAYER M3 ;
        RECT  13.284 21.563 13.302 21.6 ;
    END
  END b[6]
  PIN b[70]
    DIRECTION OUTPUT ;
    USE SIGNAL ;
    PORT
      LAYER M5 ;
        RECT  16.944 21.516 16.968 21.6 ;
    END
  END b[70]
  PIN b[71]
    DIRECTION OUTPUT ;
    USE SIGNAL ;
    PORT
      LAYER M5 ;
        RECT  17.04 21.516 17.064 21.6 ;
    END
  END b[71]
  PIN b[72]
    DIRECTION OUTPUT ;
    USE SIGNAL ;
    PORT
      LAYER M5 ;
        RECT  17.136 21.516 17.16 21.6 ;
    END
  END b[72]
  PIN b[73]
    DIRECTION OUTPUT ;
    USE SIGNAL ;
    PORT
      LAYER M5 ;
        RECT  17.232 21.516 17.256 21.6 ;
    END
  END b[73]
  PIN b[74]
    DIRECTION OUTPUT ;
    USE SIGNAL ;
    PORT
      LAYER M5 ;
        RECT  17.328 21.516 17.352 21.6 ;
    END
  END b[74]
  PIN b[75]
    DIRECTION OUTPUT ;
    USE SIGNAL ;
    PORT
      LAYER M5 ;
        RECT  17.424 21.516 17.448 21.6 ;
    END
  END b[75]
  PIN b[76]
    DIRECTION OUTPUT ;
    USE SIGNAL ;
    PORT
      LAYER M5 ;
        RECT  17.52 21.516 17.544 21.6 ;
    END
  END b[76]
  PIN b[77]
    DIRECTION OUTPUT ;
    USE SIGNAL ;
    PORT
      LAYER M5 ;
        RECT  17.616 21.516 17.64 21.6 ;
    END
  END b[77]
  PIN b[78]
    DIRECTION OUTPUT ;
    USE SIGNAL ;
    PORT
      LAYER M5 ;
        RECT  17.712 21.516 17.736 21.6 ;
    END
  END b[78]
  PIN b[79]
    DIRECTION OUTPUT ;
    USE SIGNAL ;
    PORT
      LAYER M5 ;
        RECT  17.808 21.516 17.832 21.6 ;
    END
  END b[79]
  PIN b[7]
    DIRECTION OUTPUT ;
    USE SIGNAL ;
    PORT
      LAYER M3 ;
        RECT  13.356 21.563 13.374 21.6 ;
    END
  END b[7]
  PIN b[80]
    DIRECTION OUTPUT ;
    USE SIGNAL ;
    PORT
      LAYER M5 ;
        RECT  17.904 21.516 17.928 21.6 ;
    END
  END b[80]
  PIN b[81]
    DIRECTION OUTPUT ;
    USE SIGNAL ;
    PORT
      LAYER M5 ;
        RECT  18 21.516 18.024 21.6 ;
    END
  END b[81]
  PIN b[82]
    DIRECTION OUTPUT ;
    USE SIGNAL ;
    PORT
      LAYER M5 ;
        RECT  18.096 21.516 18.12 21.6 ;
    END
  END b[82]
  PIN b[83]
    DIRECTION OUTPUT ;
    USE SIGNAL ;
    PORT
      LAYER M5 ;
        RECT  18.192 21.516 18.216 21.6 ;
    END
  END b[83]
  PIN b[84]
    DIRECTION OUTPUT ;
    USE SIGNAL ;
    PORT
      LAYER M5 ;
        RECT  18.288 21.516 18.312 21.6 ;
    END
  END b[84]
  PIN b[85]
    DIRECTION OUTPUT ;
    USE SIGNAL ;
    PORT
      LAYER M5 ;
        RECT  18.384 21.516 18.408 21.6 ;
    END
  END b[85]
  PIN b[86]
    DIRECTION OUTPUT ;
    USE SIGNAL ;
    PORT
      LAYER M5 ;
        RECT  18.48 21.516 18.504 21.6 ;
    END
  END b[86]
  PIN b[87]
    DIRECTION OUTPUT ;
    USE SIGNAL ;
    PORT
      LAYER M5 ;
        RECT  18.576 21.516 18.6 21.6 ;
    END
  END b[87]
  PIN b[88]
    DIRECTION OUTPUT ;
    USE SIGNAL ;
    PORT
      LAYER M5 ;
        RECT  18.672 21.516 18.696 21.6 ;
    END
  END b[88]
  PIN b[89]
    DIRECTION OUTPUT ;
    USE SIGNAL ;
    PORT
      LAYER M5 ;
        RECT  18.768 21.516 18.792 21.6 ;
    END
  END b[89]
  PIN b[8]
    DIRECTION OUTPUT ;
    USE SIGNAL ;
    PORT
      LAYER M3 ;
        RECT  13.428 21.563 13.446 21.6 ;
    END
  END b[8]
  PIN b[90]
    DIRECTION OUTPUT ;
    USE SIGNAL ;
    PORT
      LAYER M5 ;
        RECT  18.864 21.516 18.888 21.6 ;
    END
  END b[90]
  PIN b[91]
    DIRECTION OUTPUT ;
    USE SIGNAL ;
    PORT
      LAYER M5 ;
        RECT  18.96 21.516 18.984 21.6 ;
    END
  END b[91]
  PIN b[92]
    DIRECTION OUTPUT ;
    USE SIGNAL ;
    PORT
      LAYER M5 ;
        RECT  19.056 21.516 19.08 21.6 ;
    END
  END b[92]
  PIN b[93]
    DIRECTION OUTPUT ;
    USE SIGNAL ;
    PORT
      LAYER M5 ;
        RECT  19.152 21.516 19.176 21.6 ;
    END
  END b[93]
  PIN b[94]
    DIRECTION OUTPUT ;
    USE SIGNAL ;
    PORT
      LAYER M5 ;
        RECT  19.248 21.516 19.272 21.6 ;
    END
  END b[94]
  PIN b[95]
    DIRECTION OUTPUT ;
    USE SIGNAL ;
    PORT
      LAYER M5 ;
        RECT  19.344 21.516 19.368 21.6 ;
    END
  END b[95]
  PIN b[96]
    DIRECTION OUTPUT ;
    USE SIGNAL ;
    PORT
      LAYER M3 ;
        RECT  15.156 21.563 15.174 21.6 ;
    END
  END b[96]
  PIN b[97]
    DIRECTION OUTPUT ;
    USE SIGNAL ;
    PORT
      LAYER M3 ;
        RECT  15.228 21.563 15.246 21.6 ;
    END
  END b[97]
  PIN b[98]
    DIRECTION OUTPUT ;
    USE SIGNAL ;
    PORT
      LAYER M3 ;
        RECT  15.3 21.563 15.318 21.6 ;
    END
  END b[98]
  PIN b[99]
    DIRECTION OUTPUT ;
    USE SIGNAL ;
    PORT
      LAYER M3 ;
        RECT  15.372 21.563 15.39 21.6 ;
    END
  END b[99]
  PIN b[9]
    DIRECTION OUTPUT ;
    USE SIGNAL ;
    PORT
      LAYER M3 ;
        RECT  13.5 21.563 13.518 21.6 ;
    END
  END b[9]
  PIN ck_o
    DIRECTION OUTPUT ;
    USE SIGNAL ;
    PORT
      LAYER M3 ;
        RECT  12.708 21.563 12.726 21.6 ;
    END
  END ck_o
  PIN ckf
    DIRECTION INPUT ;
    USE SIGNAL ;
    PORT
      LAYER M5 ;
        RECT  7.632 0 7.656 0.084 ;
    END
  END ckf
  PIN ea
    DIRECTION INPUT ;
    USE SIGNAL ;
    PORT
      LAYER M5 ;
        RECT  7.728 0 7.752 0.084 ;
    END
  END ea
  PIN eb
    DIRECTION OUTPUT ;
    USE SIGNAL ;
    PORT
      LAYER M3 ;
        RECT  12.78 21.563 12.798 21.6 ;
    END
  END eb
  PIN VDD
    DIRECTION INOUT ;
    USE POWER ;
    PORT
      LAYER M5 ;
        RECT  29.592 2.151 29.712 19.449 ;
        RECT  26.892 2.151 27.012 19.449 ;
        RECT  24.192 2.151 24.312 19.449 ;
        RECT  21.492 2.151 21.612 19.449 ;
        RECT  18.792 2.151 18.912 19.449 ;
        RECT  16.092 2.151 16.212 19.449 ;
        RECT  13.392 2.151 13.512 19.449 ;
        RECT  10.692 2.151 10.812 19.449 ;
        RECT  7.992 2.151 8.112 19.449 ;
        RECT  5.292 2.151 5.412 19.449 ;
        RECT  2.592 2.151 2.712 19.449 ;
    END
  END VDD
  PIN VSS
    DIRECTION INOUT ;
    USE GROUND ;
    PORT
      LAYER M5 ;
        RECT  29.4 2.137 29.52 19.463 ;
        RECT  26.7 2.137 26.82 19.463 ;
        RECT  24 2.137 24.12 19.463 ;
        RECT  21.3 2.137 21.42 19.463 ;
        RECT  18.6 2.137 18.72 19.463 ;
        RECT  15.9 2.137 16.02 19.463 ;
        RECT  13.2 2.137 13.32 19.463 ;
        RECT  10.5 2.137 10.62 19.463 ;
        RECT  7.8 2.137 7.92 19.463 ;
        RECT  5.1 2.137 5.22 19.463 ;
        RECT  2.4 2.137 2.52 19.463 ;
    END
  END VSS
  OBS
    LAYER RVTN ;
     RECT  2.16 2.16 30.24 2.295 ;
     RECT  2.16 2.565 30.24 2.835 ;
     RECT  2.16 3.105 30.24 3.375 ;
     RECT  2.16 3.645 30.24 3.915 ;
     RECT  2.16 4.185 30.24 4.455 ;
     RECT  2.16 4.725 30.24 4.995 ;
     RECT  2.16 5.265 30.24 5.535 ;
     RECT  2.16 5.805 30.24 6.075 ;
     RECT  2.16 6.345 30.24 6.615 ;
     RECT  2.16 6.885 30.24 7.155 ;
     RECT  2.16 7.425 30.24 7.695 ;
     RECT  2.16 7.965 30.24 8.235 ;
     RECT  2.16 8.505 30.24 8.775 ;
     RECT  2.16 9.045 30.24 9.315 ;
     RECT  2.16 9.585 30.24 9.855 ;
     RECT  2.16 10.125 30.24 10.395 ;
     RECT  2.16 10.665 30.24 10.935 ;
     RECT  2.16 11.205 30.24 11.475 ;
     RECT  2.16 11.745 30.24 12.015 ;
     RECT  2.16 12.285 30.24 12.555 ;
     RECT  2.16 12.825 30.24 13.095 ;
     RECT  2.16 13.365 30.24 13.635 ;
     RECT  2.16 13.905 30.24 14.175 ;
     RECT  2.16 14.445 30.24 14.715 ;
     RECT  2.16 14.985 30.24 15.255 ;
     RECT  2.16 15.525 30.24 15.795 ;
     RECT  2.16 16.065 30.24 16.335 ;
     RECT  2.16 16.605 30.24 16.875 ;
     RECT  2.16 17.145 30.24 17.415 ;
     RECT  2.16 17.685 30.24 17.955 ;
     RECT  2.16 18.225 30.24 18.495 ;
     RECT  2.16 18.765 30.24 19.035 ;
     RECT  2.16 19.305 30.24 19.44 ;
    LAYER RVTP ;
     RECT  2.16 2.295 30.24 2.565 ;
     RECT  2.16 2.835 30.24 3.105 ;
     RECT  2.16 3.375 30.24 3.645 ;
     RECT  2.16 3.915 30.24 4.185 ;
     RECT  2.16 4.455 30.24 4.725 ;
     RECT  2.16 4.995 30.24 5.265 ;
     RECT  2.16 5.535 30.24 5.805 ;
     RECT  2.16 6.075 30.24 6.345 ;
     RECT  2.16 6.615 30.24 6.885 ;
     RECT  2.16 7.155 30.24 7.425 ;
     RECT  2.16 7.695 30.24 7.965 ;
     RECT  2.16 8.235 30.24 8.505 ;
     RECT  2.16 8.775 30.24 9.045 ;
     RECT  2.16 9.315 30.24 9.585 ;
     RECT  2.16 9.855 30.24 10.125 ;
     RECT  2.16 10.395 30.24 10.665 ;
     RECT  2.16 10.935 30.24 11.205 ;
     RECT  2.16 11.475 30.24 11.745 ;
     RECT  2.16 12.015 30.24 12.285 ;
     RECT  2.16 12.555 30.24 12.825 ;
     RECT  2.16 13.095 30.24 13.365 ;
     RECT  2.16 13.635 30.24 13.905 ;
     RECT  2.16 14.175 30.24 14.445 ;
     RECT  2.16 14.715 30.24 14.985 ;
     RECT  2.16 15.255 30.24 15.525 ;
     RECT  2.16 15.795 30.24 16.065 ;
     RECT  2.16 16.335 30.24 16.605 ;
     RECT  2.16 16.875 30.24 17.145 ;
     RECT  2.16 17.415 30.24 17.685 ;
     RECT  2.16 17.955 30.24 18.225 ;
     RECT  2.16 18.495 30.24 18.765 ;
     RECT  2.16 19.035 30.24 19.305 ;
    LAYER M1 ;
     RECT  2.16 2.151 30.24 19.449 ;
    LAYER M2 ;
     RECT  2.16 2.151 9.463 19.449 ;
     RECT  9.463 1.962 9.679 19.449 ;
     RECT  9.679 1.881 9.931 19.449 ;
     RECT  9.211 21.546 12.659 21.564 ;
     RECT  12.595 20.628 13.027 20.646 ;
     RECT  9.931 1.764 13.099 19.449 ;
     RECT  13.099 1.764 13.351 19.53 ;
     RECT  13.351 1.764 13.567 19.602 ;
     RECT  13.027 20.556 13.567 20.646 ;
     RECT  13.567 1.764 14.351 20.646 ;
     RECT  14.351 1.926 15.323 20.646 ;
     RECT  15.323 1.926 15.395 20.574 ;
     RECT  15.395 20.511 15.467 20.574 ;
     RECT  15.467 20.556 15.611 20.574 ;
     RECT  15.395 1.926 15.655 19.53 ;
     RECT  15.511 0.036 15.691 0.054 ;
     RECT  15.691 0.036 15.971 0.126 ;
     RECT  14.359 21.546 15.971 21.564 ;
     RECT  15.655 1.728 16.043 19.53 ;
     RECT  16.043 1.728 16.295 19.449 ;
     RECT  16.295 1.8 16.655 19.449 ;
     RECT  15.971 0.036 16.807 0.054 ;
     RECT  16.807 0.036 17.087 0.126 ;
     RECT  17.087 0.036 17.339 0.054 ;
     RECT  16.655 1.926 18.239 19.449 ;
     RECT  18.239 1.962 21.659 19.449 ;
     RECT  21.659 2.151 30.24 19.449 ;
    LAYER M3 ;
     RECT  14.94 0.012 17.19 0.031 ;
     RECT  14.94 0.031 17.334 0.043 ;
     RECT  14.94 0.043 17.37 0.091 ;
     RECT  14.58 0.091 17.37 0.173 ;
     RECT  13.752 0.091 13.77 0.523 ;
     RECT  10.116 0.091 10.134 0.571 ;
     RECT  11.556 0.571 11.574 0.619 ;
     RECT  11.484 0.619 11.574 0.667 ;
     RECT  21.132 0.091 21.15 0.811 ;
     RECT  13.644 0.523 13.77 1.051 ;
     RECT  13.536 1.051 13.77 1.099 ;
     RECT  14.58 0.173 17.334 1.099 ;
     RECT  8.856 0.091 8.874 1.147 ;
     RECT  10.116 0.571 10.314 1.147 ;
     RECT  12.96 1.099 17.334 1.147 ;
     RECT  12.564 1.147 17.334 1.579 ;
     RECT  8.856 1.147 10.314 1.627 ;
     RECT  11.088 0.667 11.574 1.627 ;
     RECT  8.856 1.627 11.574 1.723 ;
     RECT  12.456 1.579 17.334 1.723 ;
     RECT  20.124 0.043 20.142 1.723 ;
     RECT  21.132 0.811 21.546 1.723 ;
     RECT  7.056 1.723 7.506 1.771 ;
     RECT  18.252 1.723 18.27 1.771 ;
     RECT  19.044 0.571 19.062 1.771 ;
     RECT  20.124 1.723 21.546 1.819 ;
     RECT  18.252 1.771 19.134 1.921 ;
     RECT  8.856 1.723 17.334 1.957 ;
     RECT  18.216 1.921 19.134 1.957 ;
     RECT  19.908 1.819 21.546 1.957 ;
     RECT  6.984 1.771 7.506 2.143 ;
     RECT  8.856 1.957 19.134 2.227 ;
     RECT  19.908 1.957 21.654 2.227 ;
     RECT  8.856 2.227 21.654 2.299 ;
     RECT  2.415 2.143 2.505 2.413 ;
     RECT  5.115 2.143 5.205 2.413 ;
     RECT  6.984 2.143 7.905 2.413 ;
     RECT  24.015 2.143 24.105 2.413 ;
     RECT  26.715 2.143 26.805 2.413 ;
     RECT  29.415 2.143 29.505 2.413 ;
     RECT  6.984 2.413 8.097 2.911 ;
     RECT  8.856 2.299 21.87 2.911 ;
     RECT  6.984 2.911 21.87 3.115 ;
     RECT  6.984 3.115 22.194 3.335 ;
     RECT  7.164 3.335 22.194 3.721 ;
     RECT  7.164 3.721 22.23 4.145 ;
     RECT  7.2 4.145 22.23 4.415 ;
     RECT  7.344 4.415 22.23 5.495 ;
     RECT  8.856 5.495 22.23 5.603 ;
     RECT  7.344 5.495 8.097 5.639 ;
     RECT  10.515 5.603 22.23 6.071 ;
     RECT  10.515 6.071 21.654 6.179 ;
     RECT  10.515 6.179 21.597 8.699 ;
     RECT  10.515 8.699 10.797 10.741 ;
     RECT  11.52 8.699 21.597 10.741 ;
     RECT  8.856 5.603 9.234 17.645 ;
     RECT  10.515 10.741 21.597 18.959 ;
     RECT  12.06 18.959 21.597 18.995 ;
     RECT  2.415 2.413 2.697 19.187 ;
     RECT  5.115 2.413 5.397 19.187 ;
     RECT  7.815 5.639 8.097 19.187 ;
     RECT  10.515 18.959 10.797 19.187 ;
     RECT  12.132 18.995 21.597 19.187 ;
     RECT  24.015 2.413 24.297 19.187 ;
     RECT  26.715 2.413 26.997 19.187 ;
     RECT  29.415 2.413 29.697 19.187 ;
     RECT  2.415 19.187 2.505 19.457 ;
     RECT  5.115 19.187 5.205 19.457 ;
     RECT  7.815 19.187 7.905 19.457 ;
     RECT  10.515 19.187 10.605 19.457 ;
     RECT  12.132 19.187 21.405 19.457 ;
     RECT  24.015 19.187 24.105 19.457 ;
     RECT  26.715 19.187 26.805 19.457 ;
     RECT  29.415 19.187 29.505 19.457 ;
     RECT  12.132 19.457 20.79 20.237 ;
     RECT  20.772 20.237 20.79 20.477 ;
     RECT  12.132 20.237 19.926 21.437 ;
     RECT  12.132 21.437 19.062 21.485 ;
     RECT  19.908 21.437 19.926 21.485 ;
     RECT  9.216 17.645 9.234 21.569 ;
     RECT  12.132 21.485 17.406 21.581 ;
    LAYER M4 ;
     RECT  2.408 2.148 2.512 19.452 ;
     RECT  2.512 2.418 2.704 19.182 ;
     RECT  5.108 2.148 5.212 19.452 ;
     RECT  5.212 2.418 5.404 19.182 ;
     RECT  6.853 1.728 6.929 1.752 ;
     RECT  6.929 1.728 7.012 1.8 ;
     RECT  7.012 1.728 7.189 1.848 ;
     RECT  7.189 1.728 7.333 1.944 ;
     RECT  7.333 1.728 7.34 2.856 ;
     RECT  7.34 1.728 7.381 3.576 ;
     RECT  7.381 1.728 7.571 4.344 ;
     RECT  7.571 2.148 7.808 4.344 ;
     RECT  7.621 9.84 7.808 9.864 ;
     RECT  7.808 2.148 7.912 19.452 ;
     RECT  7.912 2.418 8.104 19.182 ;
     RECT  8.104 5.184 8.165 5.208 ;
     RECT  7.717 0.096 8.885 0.12 ;
     RECT  8.104 3.12 9.137 3.816 ;
     RECT  9.565 1.152 9.781 1.176 ;
     RECT  9.781 1.152 9.925 1.752 ;
     RECT  9.137 3.12 9.925 3.768 ;
     RECT  10.105 0.096 10.285 0.12 ;
     RECT  9.925 1.152 10.285 3.768 ;
     RECT  9.889 5.568 10.357 5.592 ;
     RECT  10.285 0.096 10.508 3.768 ;
     RECT  10.357 5.568 10.508 5.88 ;
     RECT  8.104 9.84 10.508 9.864 ;
     RECT  10.508 0.096 10.612 19.452 ;
     RECT  10.612 0.096 10.804 19.182 ;
     RECT  10.804 0.096 10.931 3.144 ;
     RECT  10.931 1.68 11.027 3.144 ;
     RECT  10.804 4.56 11.189 5.88 ;
     RECT  10.931 0.096 11.507 0.696 ;
     RECT  11.507 0.576 11.629 0.696 ;
     RECT  11.797 7.392 11.845 7.512 ;
     RECT  11.629 0.624 11.891 0.696 ;
     RECT  11.845 6.912 11.891 7.512 ;
     RECT  11.891 6.912 11.989 7.464 ;
     RECT  11.027 1.728 12.092 3.144 ;
     RECT  11.989 8.544 12.121 8.568 ;
     RECT  12.092 1.728 12.179 3.432 ;
     RECT  11.189 4.56 12.409 5.592 ;
     RECT  11.989 6.816 12.409 7.464 ;
     RECT  11.891 0.672 12.445 0.696 ;
     RECT  12.179 1.728 12.445 3.048 ;
     RECT  12.409 4.56 12.509 7.464 ;
     RECT  12.301 18.624 12.697 18.648 ;
     RECT  12.668 21.504 12.755 21.528 ;
     RECT  12.121 8.448 12.805 8.568 ;
     RECT  10.804 9.84 12.805 9.864 ;
     RECT  12.445 0.672 12.901 3.048 ;
     RECT  12.764 17.616 12.997 17.64 ;
     RECT  12.697 18.624 12.997 19.368 ;
     RECT  12.997 17.616 13.093 19.368 ;
     RECT  12.901 0.144 13.208 3.048 ;
     RECT  12.509 4.512 13.208 7.464 ;
     RECT  12.805 8.448 13.208 9.864 ;
     RECT  13.093 17.088 13.208 19.368 ;
     RECT  13.093 21.456 13.285 21.48 ;
     RECT  13.208 0.144 13.477 19.452 ;
     RECT  13.477 0.144 13.504 19.56 ;
     RECT  13.504 0.144 13.601 8.184 ;
     RECT  13.601 5.568 13.619 8.184 ;
     RECT  13.285 21.216 13.619 21.48 ;
     RECT  13.504 14.496 13.645 14.808 ;
     RECT  13.619 21.216 13.667 21.336 ;
     RECT  13.601 0.144 13.741 4.536 ;
     RECT  13.724 20.544 13.811 20.568 ;
     RECT  13.504 15.888 14.173 19.56 ;
     RECT  14.173 15.888 14.291 19.992 ;
     RECT  13.645 14.496 14.533 14.52 ;
     RECT  13.504 9.84 14.609 9.864 ;
     RECT  13.619 5.712 14.645 8.184 ;
     RECT  13.741 0.096 14.675 4.536 ;
     RECT  14.533 13.68 14.725 14.52 ;
     RECT  14.725 13.68 14.821 14.664 ;
     RECT  14.291 15.888 14.821 19.368 ;
     RECT  14.821 13.68 14.825 19.368 ;
     RECT  14.675 1.728 14.857 4.536 ;
     RECT  14.645 5.712 14.857 5.784 ;
     RECT  14.629 9.696 14.917 9.816 ;
     RECT  14.645 6.768 15.013 8.184 ;
     RECT  14.917 9.408 15.013 9.816 ;
     RECT  14.825 14.4 15.361 19.368 ;
     RECT  14.675 0.096 15.541 0.6 ;
     RECT  15.397 21.456 15.685 21.48 ;
     RECT  15.685 21.408 15.733 21.48 ;
     RECT  14.857 1.728 15.793 5.784 ;
     RECT  15.013 6.768 15.793 9.816 ;
     RECT  15.301 11.952 15.865 11.976 ;
     RECT  15.793 1.728 15.908 9.816 ;
     RECT  15.865 11.952 15.908 12.552 ;
     RECT  15.361 14.4 15.908 19.992 ;
     RECT  15.908 1.728 15.973 19.992 ;
     RECT  15.733 21.312 15.973 21.48 ;
     RECT  15.541 0.048 16.121 0.6 ;
     RECT  15.973 1.728 16.204 21.48 ;
     RECT  16.204 14.4 16.481 15.48 ;
     RECT  16.204 1.728 16.805 9.816 ;
     RECT  16.805 8.256 17.027 9.816 ;
     RECT  16.121 0.576 17.029 0.6 ;
     RECT  16.805 1.728 17.029 6.984 ;
     RECT  16.204 17.088 17.123 17.208 ;
     RECT  17.123 17.088 17.171 17.112 ;
     RECT  17.029 0.576 17.221 6.984 ;
     RECT  17.221 0.144 17.341 6.984 ;
     RECT  16.204 12.528 17.459 12.552 ;
     RECT  16.204 18.24 18.341 21.48 ;
     RECT  17.341 0.048 18.421 6.984 ;
     RECT  17.027 8.784 18.421 9.672 ;
     RECT  18.421 0.048 18.608 9.672 ;
     RECT  17.605 11.952 18.608 11.976 ;
     RECT  17.509 13.104 18.608 13.128 ;
     RECT  16.481 14.496 18.608 15.48 ;
     RECT  17.701 16.56 18.608 16.632 ;
     RECT  18.341 18.192 18.608 21.48 ;
     RECT  18.608 0.048 18.904 21.48 ;
     RECT  18.904 14.928 18.965 14.952 ;
     RECT  18.904 7.92 19.037 7.944 ;
     RECT  18.904 6.816 19.043 6.84 ;
     RECT  18.904 8.976 19.043 9.528 ;
     RECT  18.904 19.392 19.187 21.48 ;
     RECT  19.043 9.504 19.397 9.528 ;
     RECT  18.904 0.048 19.433 5.064 ;
     RECT  19.187 20.208 19.829 21.48 ;
     RECT  19.433 0.048 19.937 4.728 ;
     RECT  19.829 21.456 19.937 21.48 ;
     RECT  19.937 0.048 20.153 4.584 ;
     RECT  19.829 20.208 20.225 20.472 ;
     RECT  20.225 20.448 20.801 20.472 ;
     RECT  20.153 0.096 20.837 4.584 ;
     RECT  20.837 0.096 21.161 0.84 ;
     RECT  20.837 1.968 21.308 4.584 ;
     RECT  21.308 1.968 21.412 19.452 ;
     RECT  21.412 1.968 21.485 19.182 ;
     RECT  21.161 0.816 21.557 0.84 ;
     RECT  21.485 2.418 21.604 19.182 ;
     RECT  21.604 3.12 22.205 3.144 ;
     RECT  24.008 2.148 24.112 19.452 ;
     RECT  24.112 2.418 24.304 19.182 ;
     RECT  26.708 2.148 26.812 19.452 ;
     RECT  26.812 2.418 27.004 19.182 ;
     RECT  29.408 2.148 29.512 19.452 ;
     RECT  29.512 2.418 29.704 19.182 ;
    LAYER M5 ;
     RECT  6.864 0.016 7.752 0.131 ;
     RECT  9.936 0.016 19.08 0.133 ;
     RECT  6.864 0.131 7.656 1.763 ;
     RECT  9.936 0.133 19.128 1.763 ;
     RECT  6.96 1.763 7.656 1.811 ;
     RECT  7.056 1.811 7.656 1.859 ;
     RECT  10.5 1.763 19.128 2.099 ;
     RECT  7.44 1.859 7.656 2.137 ;
     RECT  2.4 2.137 2.52 2.151 ;
     RECT  5.1 2.137 5.22 2.151 ;
     RECT  7.44 2.137 7.92 2.151 ;
     RECT  21.3 2.137 21.42 2.151 ;
     RECT  24 2.137 24.12 2.151 ;
     RECT  26.7 2.137 26.82 2.151 ;
     RECT  29.4 2.137 29.52 2.151 ;
     RECT  14.688 2.099 19.128 2.245 ;
     RECT  7.44 2.151 8.112 2.821 ;
     RECT  21.3 2.151 21.612 3.253 ;
     RECT  10.5 2.099 13.512 3.301 ;
     RECT  14.688 2.245 19.752 3.875 ;
     RECT  10.368 3.301 13.656 4.261 ;
     RECT  14.688 3.875 18.912 4.261 ;
     RECT  7.392 2.821 8.112 4.355 ;
     RECT  21.072 3.253 21.612 4.595 ;
     RECT  10.368 4.261 18.912 5.029 ;
     RECT  10.368 5.029 19.032 5.171 ;
     RECT  10.368 5.171 10.812 5.891 ;
     RECT  11.856 5.171 19.032 6.995 ;
     RECT  11.856 6.995 13.512 7.523 ;
     RECT  12 7.523 13.512 8.579 ;
     RECT  14.688 6.995 19.032 9.011 ;
     RECT  14.688 9.011 18.912 9.685 ;
     RECT  7.632 4.355 8.112 9.875 ;
     RECT  14.64 9.685 18.912 13.669 ;
     RECT  12.816 8.579 13.512 14.485 ;
     RECT  14.544 13.669 18.912 14.485 ;
     RECT  12.816 14.485 18.912 19.333 ;
     RECT  12.72 19.333 18.912 19.381 ;
     RECT  2.4 2.151 2.712 19.449 ;
     RECT  5.1 2.151 5.412 19.449 ;
     RECT  7.8 9.875 8.112 19.449 ;
     RECT  10.5 5.891 10.812 19.449 ;
     RECT  21.3 4.595 21.612 19.449 ;
     RECT  24 2.151 24.312 19.449 ;
     RECT  26.7 2.151 27.012 19.449 ;
     RECT  29.4 2.151 29.712 19.449 ;
     RECT  2.4 19.449 2.52 19.463 ;
     RECT  5.1 19.449 5.22 19.463 ;
     RECT  7.8 19.449 7.92 19.463 ;
     RECT  10.5 19.449 10.62 19.463 ;
     RECT  21.3 19.449 21.42 19.463 ;
     RECT  24 19.449 24.12 19.463 ;
     RECT  26.7 19.449 26.82 19.463 ;
     RECT  29.4 19.449 29.52 19.463 ;
     RECT  12.72 19.381 19.176 20.437 ;
     RECT  12.72 20.437 19.272 21.445 ;
     RECT  12.72 21.445 19.368 21.539 ;
     RECT  13.296 21.539 19.368 21.584 ;
  END
END hbfd_lh_136_SN
END LIBRARY
